VERSION 5.7 ;
BUSBITCHARS "[]" ;
DIVIDERCHAR "/" ;

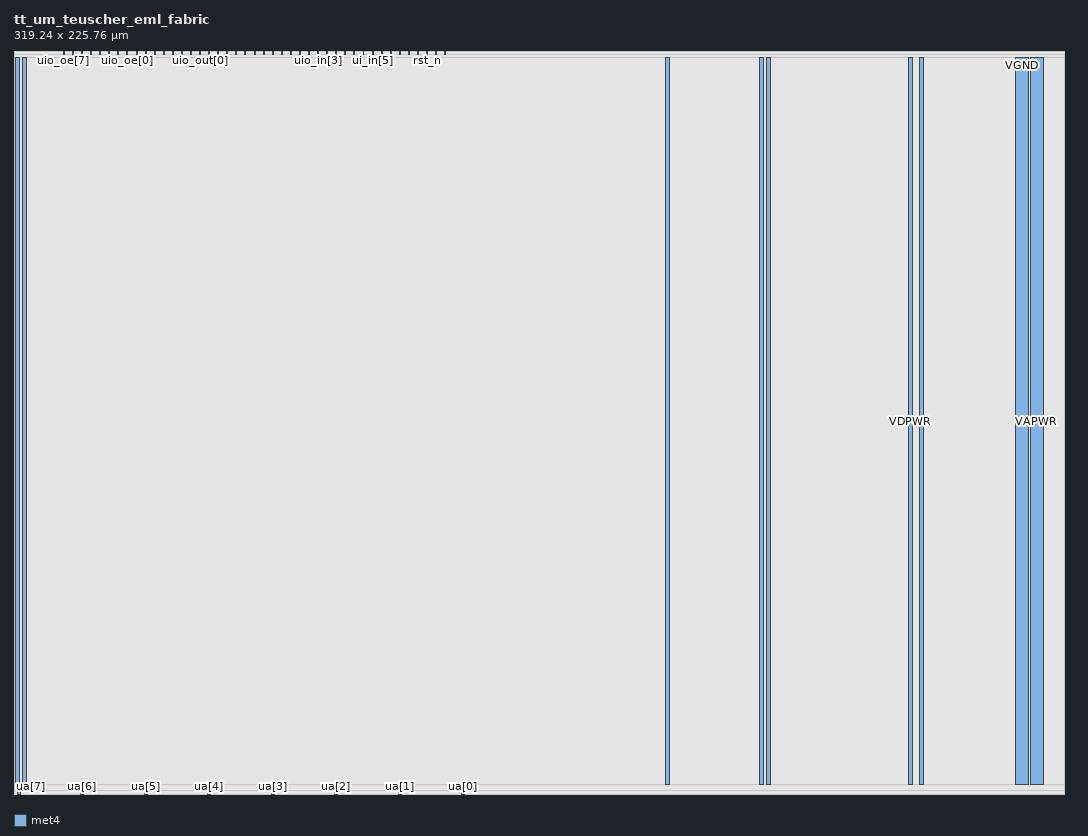
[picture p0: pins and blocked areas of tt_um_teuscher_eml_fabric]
MACRO tt_um_teuscher_eml_fabric
  CLASS BLOCK ;
  ORIGIN 0 0 ;
  FOREIGN tt_um_teuscher_eml_fabric 0 0 ;
  SIZE 319.240 BY 225.760 ;
  PIN clk
    DIRECTION INPUT ;
    USE SIGNAL ;
    PORT
      LAYER met4 ;
        RECT 128.190 224.760 128.490 225.760 ;
    END
  END clk
  PIN ena
    DIRECTION INPUT ;
    USE SIGNAL ;
    PORT
      LAYER met4 ;
        RECT 130.950 224.760 131.250 225.760 ;
    END
  END ena
  PIN rst_n
    DIRECTION INPUT ;
    USE SIGNAL ;
    PORT
      LAYER met4 ;
        RECT 125.430 224.760 125.730 225.760 ;
    END
  END rst_n
  PIN ua[0]
    DIRECTION INOUT ;
    USE SIGNAL ;
    PORT
      LAYER met4 ;
        RECT 136.170 0.000 137.070 1.000 ;
    END
  END ua[0]
  PIN ua[1]
    DIRECTION INOUT ;
    USE SIGNAL ;
    PORT
      LAYER met4 ;
        RECT 116.850 0.000 117.750 1.000 ;
    END
  END ua[1]
  PIN ua[2]
    DIRECTION INOUT ;
    USE SIGNAL ;
    PORT
      LAYER met4 ;
        RECT 97.530 0.000 98.430 1.000 ;
    END
  END ua[2]
  PIN ua[3]
    DIRECTION INOUT ;
    USE SIGNAL ;
    PORT
      LAYER met4 ;
        RECT 78.210 0.000 79.110 1.000 ;
    END
  END ua[3]
  PIN ua[4]
    DIRECTION INOUT ;
    USE SIGNAL ;
    PORT
      LAYER met4 ;
        RECT 58.890 0.000 59.790 1.000 ;
    END
  END ua[4]
  PIN ua[5]
    DIRECTION INOUT ;
    USE SIGNAL ;
    PORT
      LAYER met4 ;
        RECT 39.570 0.000 40.470 1.000 ;
    END
  END ua[5]
  PIN ua[6]
    DIRECTION INOUT ;
    USE SIGNAL ;
    PORT
      LAYER met4 ;
        RECT 20.250 0.000 21.150 1.000 ;
    END
  END ua[6]
  PIN ua[7]
    DIRECTION INOUT ;
    USE SIGNAL ;
    PORT
      LAYER met4 ;
        RECT 0.930 0.000 1.830 1.000 ;
    END
  END ua[7]
  PIN ui_in[0]
    DIRECTION INPUT ;
    USE SIGNAL ;
    PORT
      LAYER met4 ;
        RECT 122.670 224.760 122.970 225.760 ;
    END
  END ui_in[0]
  PIN ui_in[1]
    DIRECTION INPUT ;
    USE SIGNAL ;
    PORT
      LAYER met4 ;
        RECT 119.910 224.760 120.210 225.760 ;
    END
  END ui_in[1]
  PIN ui_in[2]
    DIRECTION INPUT ;
    USE SIGNAL ;
    PORT
      LAYER met4 ;
        RECT 117.150 224.760 117.450 225.760 ;
    END
  END ui_in[2]
  PIN ui_in[3]
    DIRECTION INPUT ;
    USE SIGNAL ;
    PORT
      LAYER met4 ;
        RECT 114.390 224.760 114.690 225.760 ;
    END
  END ui_in[3]
  PIN ui_in[4]
    DIRECTION INPUT ;
    USE SIGNAL ;
    PORT
      LAYER met4 ;
        RECT 111.630 224.760 111.930 225.760 ;
    END
  END ui_in[4]
  PIN ui_in[5]
    DIRECTION INPUT ;
    USE SIGNAL ;
    PORT
      LAYER met4 ;
        RECT 108.870 224.760 109.170 225.760 ;
    END
  END ui_in[5]
  PIN ui_in[6]
    DIRECTION INPUT ;
    USE SIGNAL ;
    PORT
      LAYER met4 ;
        RECT 106.110 224.760 106.410 225.760 ;
    END
  END ui_in[6]
  PIN ui_in[7]
    DIRECTION INPUT ;
    USE SIGNAL ;
    PORT
      LAYER met4 ;
        RECT 103.350 224.760 103.650 225.760 ;
    END
  END ui_in[7]
  PIN uio_in[0]
    DIRECTION INPUT ;
    USE SIGNAL ;
    PORT
      LAYER met4 ;
        RECT 100.590 224.760 100.890 225.760 ;
    END
  END uio_in[0]
  PIN uio_in[1]
    DIRECTION INPUT ;
    USE SIGNAL ;
    PORT
      LAYER met4 ;
        RECT 97.830 224.760 98.130 225.760 ;
    END
  END uio_in[1]
  PIN uio_in[2]
    DIRECTION INPUT ;
    USE SIGNAL ;
    PORT
      LAYER met4 ;
        RECT 95.070 224.760 95.370 225.760 ;
    END
  END uio_in[2]
  PIN uio_in[3]
    DIRECTION INPUT ;
    USE SIGNAL ;
    PORT
      LAYER met4 ;
        RECT 92.310 224.760 92.610 225.760 ;
    END
  END uio_in[3]
  PIN uio_in[4]
    DIRECTION INPUT ;
    USE SIGNAL ;
    PORT
      LAYER met4 ;
        RECT 89.550 224.760 89.850 225.760 ;
    END
  END uio_in[4]
  PIN uio_in[5]
    DIRECTION INPUT ;
    USE SIGNAL ;
    PORT
      LAYER met4 ;
        RECT 86.790 224.760 87.090 225.760 ;
    END
  END uio_in[5]
  PIN uio_in[6]
    DIRECTION INPUT ;
    USE SIGNAL ;
    PORT
      LAYER met4 ;
        RECT 84.030 224.760 84.330 225.760 ;
    END
  END uio_in[6]
  PIN uio_in[7]
    DIRECTION INPUT ;
    USE SIGNAL ;
    PORT
      LAYER met4 ;
        RECT 81.270 224.760 81.570 225.760 ;
    END
  END uio_in[7]
  PIN uio_oe[0]
    DIRECTION OUTPUT ;
    USE SIGNAL ;
    PORT
      LAYER met4 ;
        RECT 34.350 224.760 34.650 225.760 ;
    END
  END uio_oe[0]
  PIN uio_oe[1]
    DIRECTION OUTPUT ;
    USE SIGNAL ;
    PORT
      LAYER met4 ;
        RECT 31.590 224.760 31.890 225.760 ;
    END
  END uio_oe[1]
  PIN uio_oe[2]
    DIRECTION OUTPUT ;
    USE SIGNAL ;
    PORT
      LAYER met4 ;
        RECT 28.830 224.760 29.130 225.760 ;
    END
  END uio_oe[2]
  PIN uio_oe[3]
    DIRECTION OUTPUT ;
    USE SIGNAL ;
    PORT
      LAYER met4 ;
        RECT 26.070 224.760 26.370 225.760 ;
    END
  END uio_oe[3]
  PIN uio_oe[4]
    DIRECTION OUTPUT ;
    USE SIGNAL ;
    PORT
      LAYER met4 ;
        RECT 23.310 224.760 23.610 225.760 ;
    END
  END uio_oe[4]
  PIN uio_oe[5]
    DIRECTION OUTPUT ;
    USE SIGNAL ;
    PORT
      LAYER met4 ;
        RECT 20.550 224.760 20.850 225.760 ;
    END
  END uio_oe[5]
  PIN uio_oe[6]
    DIRECTION OUTPUT ;
    USE SIGNAL ;
    PORT
      LAYER met4 ;
        RECT 17.790 224.760 18.090 225.760 ;
    END
  END uio_oe[6]
  PIN uio_oe[7]
    DIRECTION OUTPUT ;
    USE SIGNAL ;
    PORT
      LAYER met4 ;
        RECT 15.030 224.760 15.330 225.760 ;
    END
  END uio_oe[7]
  PIN uio_out[0]
    DIRECTION OUTPUT ;
    USE SIGNAL ;
    PORT
      LAYER met4 ;
        RECT 56.430 224.760 56.730 225.760 ;
    END
  END uio_out[0]
  PIN uio_out[1]
    DIRECTION OUTPUT ;
    USE SIGNAL ;
    PORT
      LAYER met4 ;
        RECT 53.670 224.760 53.970 225.760 ;
    END
  END uio_out[1]
  PIN uio_out[2]
    DIRECTION OUTPUT ;
    USE SIGNAL ;
    PORT
      LAYER met4 ;
        RECT 50.910 224.760 51.210 225.760 ;
    END
  END uio_out[2]
  PIN uio_out[3]
    DIRECTION OUTPUT ;
    USE SIGNAL ;
    PORT
      LAYER met4 ;
        RECT 48.150 224.760 48.450 225.760 ;
    END
  END uio_out[3]
  PIN uio_out[4]
    DIRECTION OUTPUT ;
    USE SIGNAL ;
    PORT
      LAYER met4 ;
        RECT 45.390 224.760 45.690 225.760 ;
    END
  END uio_out[4]
  PIN uio_out[5]
    DIRECTION OUTPUT ;
    USE SIGNAL ;
    PORT
      LAYER met4 ;
        RECT 42.630 224.760 42.930 225.760 ;
    END
  END uio_out[5]
  PIN uio_out[6]
    DIRECTION OUTPUT ;
    USE SIGNAL ;
    PORT
      LAYER met4 ;
        RECT 39.870 224.760 40.170 225.760 ;
    END
  END uio_out[6]
  PIN uio_out[7]
    DIRECTION OUTPUT ;
    USE SIGNAL ;
    PORT
      LAYER met4 ;
        RECT 37.110 224.760 37.410 225.760 ;
    END
  END uio_out[7]
  PIN uo_out[0]
    DIRECTION OUTPUT ;
    USE SIGNAL ;
    PORT
      LAYER met4 ;
        RECT 78.510 224.760 78.810 225.760 ;
    END
  END uo_out[0]
  PIN uo_out[1]
    DIRECTION OUTPUT ;
    USE SIGNAL ;
    PORT
      LAYER met4 ;
        RECT 75.750 224.760 76.050 225.760 ;
    END
  END uo_out[1]
  PIN uo_out[2]
    DIRECTION OUTPUT ;
    USE SIGNAL ;
    PORT
      LAYER met4 ;
        RECT 72.990 224.760 73.290 225.760 ;
    END
  END uo_out[2]
  PIN uo_out[3]
    DIRECTION OUTPUT ;
    USE SIGNAL ;
    PORT
      LAYER met4 ;
        RECT 70.230 224.760 70.530 225.760 ;
    END
  END uo_out[3]
  PIN uo_out[4]
    DIRECTION OUTPUT ;
    USE SIGNAL ;
    PORT
      LAYER met4 ;
        RECT 67.470 224.760 67.770 225.760 ;
    END
  END uo_out[4]
  PIN uo_out[5]
    DIRECTION OUTPUT ;
    USE SIGNAL ;
    PORT
      LAYER met4 ;
        RECT 64.710 224.760 65.010 225.760 ;
    END
  END uo_out[5]
  PIN uo_out[6]
    DIRECTION OUTPUT ;
    USE SIGNAL ;
    PORT
      LAYER met4 ;
        RECT 61.950 224.760 62.250 225.760 ;
    END
  END uo_out[6]
  PIN uo_out[7]
    DIRECTION OUTPUT ;
    USE SIGNAL ;
    PORT
      LAYER met4 ;
        RECT 59.190 224.760 59.490 225.760 ;
    END
  END uo_out[7]
  PIN VGND
    DIRECTION INOUT ;
    USE GROUND ;
    PORT
      LAYER met4 ;
        RECT 0.600 3.000 1.800 223.800 ;
        RECT 228.800 3.000 230.000 223.800 ;
        RECT 304.400 3.000 308.400 223.800 ;
    END
  END VGND
  PIN VAPWR
    DIRECTION INOUT ;
    USE POWER ;
    PORT
      LAYER met4 ;
        RECT 2.600 3.000 3.800 223.800 ;
        RECT 198.100 3.000 199.300 223.800 ;
        RECT 226.800 3.000 228.000 223.800 ;
        RECT 275.200 3.000 276.400 223.800 ;
        RECT 309.000 3.000 313.000 223.800 ;
    END
  END VAPWR
  PIN VDPWR
    DIRECTION INOUT ;
    USE POWER ;
    PORT
      LAYER met4 ;
        RECT 271.900 3.000 273.100 223.800 ;
    END
  END VDPWR
  OBS
    LAYER met1 ;
      RECT 0.000 0.000 319.240 225.760 ;
    LAYER met2 ;
      RECT 0.000 0.000 319.240 225.760 ;
    LAYER met3 ;
      RECT 0.000 0.000 319.240 225.760 ;
    LAYER met4 ;
      RECT 0.000 0.000 0.930 1.000 ;
      RECT 1.830 0.000 20.250 1.000 ;
      RECT 21.150 0.000 39.570 1.000 ;
      RECT 40.470 0.000 58.890 1.000 ;
      RECT 59.790 0.000 78.210 1.000 ;
      RECT 79.110 0.000 97.530 1.000 ;
      RECT 98.430 0.000 116.850 1.000 ;
      RECT 117.750 0.000 136.170 1.000 ;
      RECT 137.070 0.000 319.240 1.000 ;
      RECT 0.000 1.000 319.240 3.000 ;
      RECT 0.000 3.000 0.600 223.800 ;
      RECT 1.800 3.000 2.600 223.800 ;
      RECT 3.800 3.000 198.100 223.800 ;
      RECT 199.300 3.000 226.800 223.800 ;
      RECT 228.000 3.000 228.800 223.800 ;
      RECT 230.000 3.000 271.900 223.800 ;
      RECT 273.100 3.000 275.200 223.800 ;
      RECT 276.400 3.000 304.400 223.800 ;
      RECT 308.400 3.000 309.000 223.800 ;
      RECT 313.000 3.000 319.240 223.800 ;
      RECT 0.000 223.800 319.240 224.760 ;
      RECT 0.000 224.760 15.030 225.760 ;
      RECT 15.330 224.760 17.790 225.760 ;
      RECT 18.090 224.760 20.550 225.760 ;
      RECT 20.850 224.760 23.310 225.760 ;
      RECT 23.610 224.760 26.070 225.760 ;
      RECT 26.370 224.760 28.830 225.760 ;
      RECT 29.130 224.760 31.590 225.760 ;
      RECT 31.890 224.760 34.350 225.760 ;
      RECT 34.650 224.760 37.110 225.760 ;
      RECT 37.410 224.760 39.870 225.760 ;
      RECT 40.170 224.760 42.630 225.760 ;
      RECT 42.930 224.760 45.390 225.760 ;
      RECT 45.690 224.760 48.150 225.760 ;
      RECT 48.450 224.760 50.910 225.760 ;
      RECT 51.210 224.760 53.670 225.760 ;
      RECT 53.970 224.760 56.430 225.760 ;
      RECT 56.730 224.760 59.190 225.760 ;
      RECT 59.490 224.760 61.950 225.760 ;
      RECT 62.250 224.760 64.710 225.760 ;
      RECT 65.010 224.760 67.470 225.760 ;
      RECT 67.770 224.760 70.230 225.760 ;
      RECT 70.530 224.760 72.990 225.760 ;
      RECT 73.290 224.760 75.750 225.760 ;
      RECT 76.050 224.760 78.510 225.760 ;
      RECT 78.810 224.760 81.270 225.760 ;
      RECT 81.570 224.760 84.030 225.760 ;
      RECT 84.330 224.760 86.790 225.760 ;
      RECT 87.090 224.760 89.550 225.760 ;
      RECT 89.850 224.760 92.310 225.760 ;
      RECT 92.610 224.760 95.070 225.760 ;
      RECT 95.370 224.760 97.830 225.760 ;
      RECT 98.130 224.760 100.590 225.760 ;
      RECT 100.890 224.760 103.350 225.760 ;
      RECT 103.650 224.760 106.110 225.760 ;
      RECT 106.410 224.760 108.870 225.760 ;
      RECT 109.170 224.760 111.630 225.760 ;
      RECT 111.930 224.760 114.390 225.760 ;
      RECT 114.690 224.760 117.150 225.760 ;
      RECT 117.450 224.760 119.910 225.760 ;
      RECT 120.210 224.760 122.670 225.760 ;
      RECT 122.970 224.760 125.430 225.760 ;
      RECT 125.730 224.760 128.190 225.760 ;
      RECT 128.490 224.760 130.950 225.760 ;
      RECT 131.250 224.760 319.240 225.760 ;
  END
END tt_um_teuscher_eml_fabric

END LIBRARY
